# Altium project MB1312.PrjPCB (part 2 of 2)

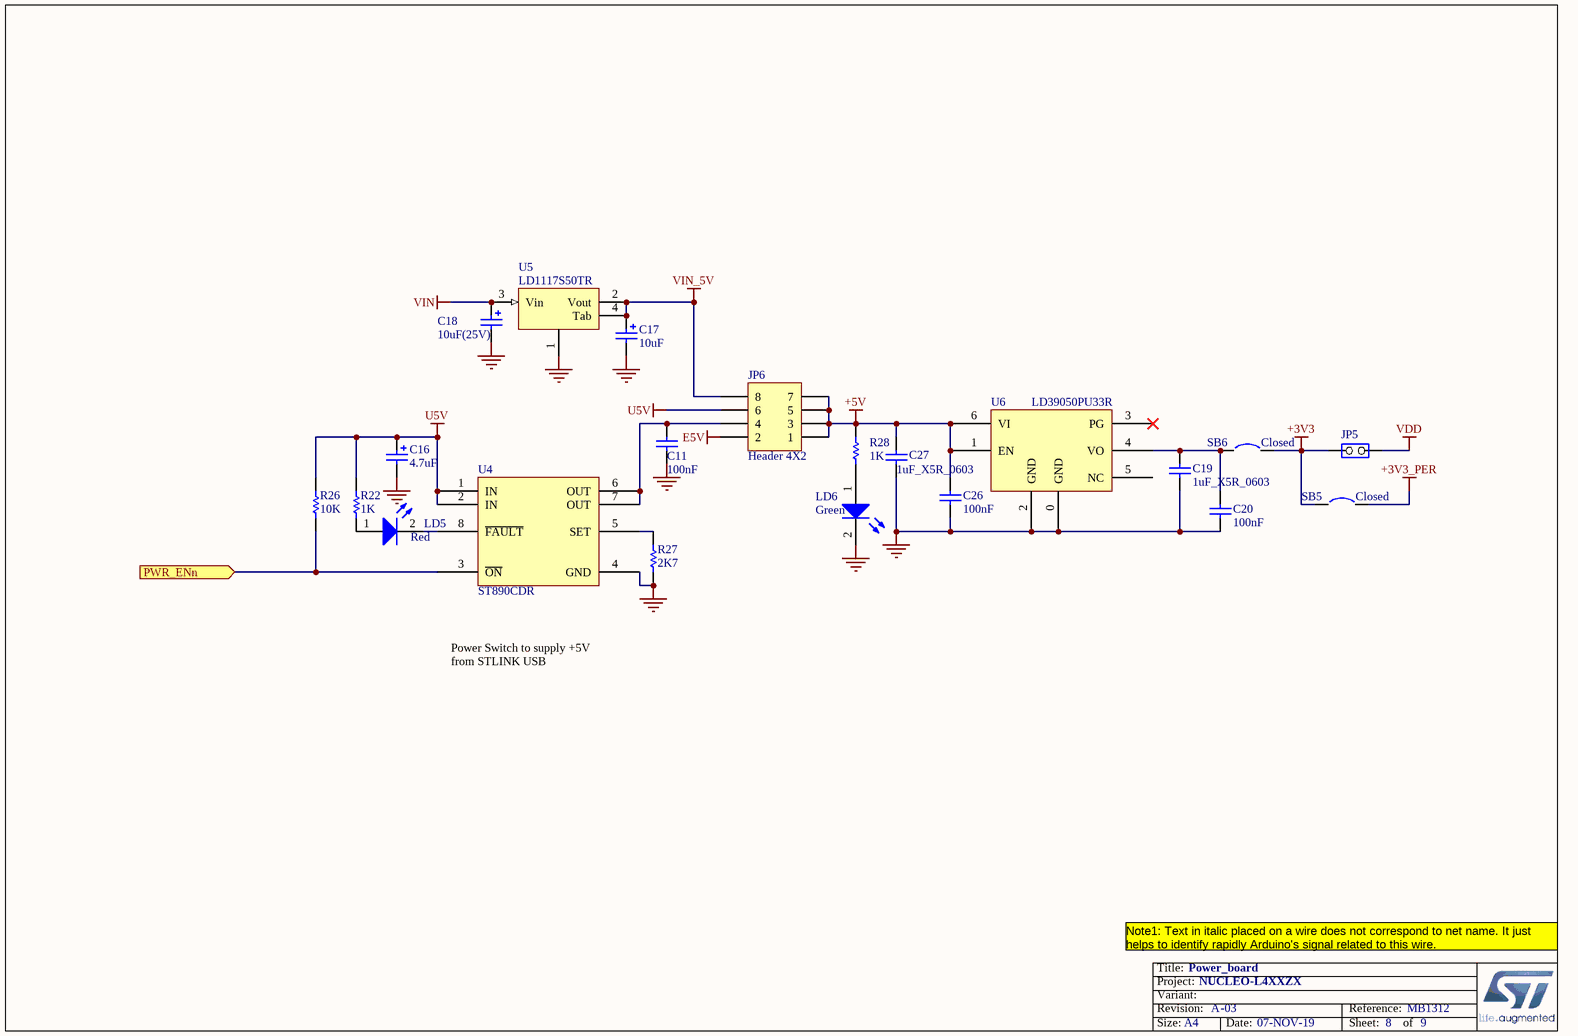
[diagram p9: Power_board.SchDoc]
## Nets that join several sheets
+3V3: Connectors (CN8.7 CN11.16 SB111.1), Power_board (JP5.1 SB5.1 SB6.2)
+3V3_PER: Connectors (SB110.1 U8.5), ST-Link_V2-1 (R23.1), USB (R41.2 R45.2 R51.1), Power_board (SB5.2)
+5V: Connectors (CN8.9 CN11.18), ST-Link_V2-1 (D2.1), USB (U12.5), Power_board (9 pins)
AGND: Connectors (C45.2 CN10.3 CN12.32), STM32_microcontroller_power (7 pins)
AVDD: Connectors (CN10.1), STM32_microcontroller_power (5 pins)
E5V: Connectors (CN11.6), ST-Link_V2-1 (D3.1), Power_board (JP6.2)
GND: Connectors (27 pins), Power_SMPS (27 pins), ST-Link_V2-1 (48 pins), USB (15 pins), STM32_microcontroller_IOs (7 pins), STM32_microcontroller_power (33 pins), Power_board (14 pins)
U5V: Connectors (CN12.8), ST-Link_V2-1 (5 pins), Power_board (6 pins)
VBAT: Connectors (CN11.33), STM32_microcontroller_power (C60.1 SB154.2 U11.6)
VDD: Connectors (CN11.5), Power_SMPS (5 pins), STM32_microcontroller_power (8 pins), Power_board (JP5.2)
VDD_1V2: Power_SMPS (SB2.2 SB3.1 SB11.2), STM32_microcontroller_IOs (C39.2 C55.2 SB15.2 SB139.2)
VDD_MCU: Connectors (SB112.1), Power_SMPS (SB19.2 SB122.2 SB127.2), ST-Link_V2-1 (C44.1 U14.8), STM32_microcontroller_IOs (B1.2 B1.3 R44.1), STM32_microcontroller_power (21 pins)
VIN: Connectors (CN8.15 CN11.24), Power_board (C18.1 U5.3)
VIN_5V: ST-Link_V2-1 (D4.1), Power_board (C17.1 JP6.8 U5.2 U5.4)
VREF+: Connectors (C45.1 SB119.1), STM32_microcontroller_power (C56.1 C57.1 SB149.2 U11.32)
MCO: ST-Link_V2-1 (SB109.1), STM32_microcontroller_power (SB148.2)
NetC42_1: USB (6 pins), STM32_microcontroller_IOs (R54.1)
NetCN6_1: ST-Link_V2-1 (CN6.1 U2.13), STM32_microcontroller_IOs (SB131.2)
NetCN6_2: ST-Link_V2-1 (CN6.2 U2.12), STM32_microcontroller_IOs (SB130.2)
NetCN14_2: USB (CN14.2 U13.1 U13.6), STM32_microcontroller_IOs (SB142.1)
NetCN14_3: USB (CN14.3 R50.1 U13.3 U13.4), STM32_microcontroller_IOs (SB143.1)
NetCN14_4: USB (CN14.4 D6.1), STM32_microcontroller_IOs (SB134.1)
NetR26_2: ST-Link_V2-1 (U2.28), Power_board (R26.2 U4.3)
NRST: Connectors (CN8.5 CN11.14), ST-Link_V2-1 (JP3.2), STM32_microcontroller_power (B2.2 B2.3 C41.2 U11.25)
PA0: Connectors (CN11.28 SB179.1), STM32_microcontroller_IOs (SB178.2 U11.34)
PA1: Connectors (CN10.11 CN11.30), STM32_microcontroller_IOs (U11.35)
PA2: Connectors (CN12.35 SB150.1), STM32_microcontroller_IOs (U11.36)
PA3: Connectors (CN9.1 CN12.37), STM32_microcontroller_IOs (U11.37)
PA4: Connectors (CN11.32 SB126.1 SB133.1), STM32_microcontroller_IOs (U11.40)
PA5: Connectors (CN7.10 CN12.11 SB123.2), STM32_microcontroller_IOs (U11.41)
PA6: Connectors (CN7.12 CN12.13), STM32_microcontroller_IOs (U11.42)
PA7: Connectors (CN7.14 CN12.15), STM32_microcontroller_IOs (U11.43)
PA8: Connectors (CN12.23), STM32_microcontroller_IOs (TP1.1 U11.100)
PA9: Connectors (CN12.21), STM32_microcontroller_IOs (SB135.2 U11.101)
PA10: Connectors (CN12.33), STM32_microcontroller_IOs (SB134.2 U11.102)
PA11: Connectors (CN12.14), STM32_microcontroller_IOs (SB142.2 U11.103)
PA12: Connectors (CN12.12), STM32_microcontroller_IOs (SB143.2 U11.104)
PA13: Connectors (CN11.13), ST-Link_V2-1 (SB106.1), STM32_microcontroller_IOs (U11.105)
PA14: Connectors (CN11.15), ST-Link_V2-1 (SB102.1), STM32_microcontroller_IOs (U11.109)
PA15: Connectors (CN11.17), STM32_microcontroller_IOs (U11.110)
PB0: Connectors (SB144.2 SB159.1 SB182.1), STM32_microcontroller_IOs (U11.46)
PB1: Connectors (CN10.7 CN12.24), STM32_microcontroller_IOs (U11.47)
PB2: Connectors (CN9.13 CN12.22), STM32_microcontroller_IOs (U11.48)
PB3: Connectors (CN7.15 CN12.31), ST-Link_V2-1 (SB141.2), STM32_microcontroller_IOs (SB161.2 SB162.2)
PB4: Connectors (CN12.27 SB128.1 SB140.1), STM32_microcontroller_IOs (SB163.2 SB164.2)
PB5: Connectors (CN7.13 CN12.29), STM32_microcontroller_IOs (SB165.2 SB176.2)
PB6: Connectors (CN9.15 CN12.17), STM32_microcontroller_IOs (SB174.2 SB175.2)
PB7: Connectors (CN11.21), STM32_microcontroller_IOs (R30.1 SB172.2 SB173.2)
PB8: Connectors (CN7.2 CN12.3 SB153.2), STM32_microcontroller_IOs (SB181.2), STM32_microcontroller_power (SB184.2)
PB9: Connectors (CN7.4 CN12.5 SB151.2), STM32_microcontroller_IOs (SB185.2 SB186.2)
PB10: Connectors (CN12.25 SB155.1 SB188.2), STM32_microcontroller_IOs (U11.69)
PB11: Connectors (CN10.34 CN12.18), STM32_microcontroller_IOs (SB138.2)
PB12: Connectors (CN7.7 CN12.16), STM32_microcontroller_IOs (U11.73)
PB13: Connectors (CN7.5 CN12.30), STM32_microcontroller_IOs (U11.74)
PB14: Connectors (CN12.28), STM32_microcontroller_IOs (SB132.1 U11.75)
PB15: Connectors (CN7.3 CN12.26), STM32_microcontroller_IOs (U11.76)
PC0: Connectors (CN9.3 CN11.38), STM32_microcontroller_IOs (U11.26)
PC1: Connectors (CN9.7 CN11.36), STM32_microcontroller_IOs (U11.27)
PC2: Connectors (CN10.9 CN11.35), STM32_microcontroller_IOs (U11.28)
PC3: Connectors (CN9.5 CN11.37), STM32_microcontroller_IOs (U11.29)
PC4: Connectors (CN9.9 CN12.34 SB151.1), STM32_microcontroller_IOs (U11.44)
PC5: Connectors (CN9.11 CN12.6 SB153.1), STM32_microcontroller_IOs (U11.45)
PC6: Connectors (CN7.1 CN12.4), STM32_microcontroller_IOs (U11.96)
PC7: Connectors (CN12.19 SB124.1), STM32_microcontroller_IOs (U11.97)
PC8: Connectors (CN8.2 SB137.1), STM32_microcontroller_IOs (U11.98)
PC9: Connectors (CN8.4 SB136.1), STM32_microcontroller_IOs (U11.99)
PC10: Connectors (CN8.6 CN11.1), STM32_microcontroller_IOs (U11.111)
PC11: Connectors (CN8.8 CN11.2), STM32_microcontroller_IOs (U11.112)
PC12: Connectors (CN8.10 CN11.3), STM32_microcontroller_IOs (U11.113)
PC13: Connectors (CN11.23), STM32_microcontroller_IOs (SB197.1 U11.7)
PC14: Connectors (SB145.1), STM32_microcontroller_IOs (R39.2 U11.8)
PC15: Connectors (SB146.1), STM32_microcontroller_IOs (R40.2 U11.9)
PD0: Connectors (CN9.25 CN11.57), STM32_microcontroller_IOs (U11.114)
PD1: Connectors (CN9.27 CN11.55), STM32_microcontroller_IOs (U11.115)
PD2: Connectors (CN8.12 CN11.4), STM32_microcontroller_IOs (U11.116)
PD3: Connectors (CN9.10 CN11.40), STM32_microcontroller_IOs (U11.117)
PD4: Connectors (CN9.8 CN11.39), STM32_microcontroller_IOs (U11.118)
PD5: Connectors (CN9.6 CN11.41), STM32_microcontroller_IOs (U11.119)
PD6: Connectors (CN9.4 CN11.43), STM32_microcontroller_IOs (U11.122)
PD7: Connectors (CN9.2 CN11.45), STM32_microcontroller_IOs (U11.123)
PD8: Connectors (CN10.14 CN12.10), STM32_microcontroller_IOs (U11.77)
PD9: Connectors (CN10.16 CN11.69), STM32_microcontroller_IOs (U11.78)
PD10: Connectors (CN12.65), STM32_microcontroller_IOs (U11.79)
PD11: Connectors (CN12.45), STM32_microcontroller_IOs (U11.80)
PD12: Connectors (CN12.43), STM32_microcontroller_IOs (U11.81)
PD13: Connectors (CN12.41), STM32_microcontroller_IOs (U11.82)
PD14: Connectors (CN7.16 CN12.46), STM32_microcontroller_IOs (U11.85)
PD15: Connectors (CN7.18 CN12.48), STM32_microcontroller_IOs (U11.86)
PE0: Connectors (CN10.33 CN12.64), STM32_microcontroller_IOs (SB187.2 SB190.1)
PE1: Connectors (CN11.61), STM32_microcontroller_IOs (SB14.1 SB189.1)
PE2: Connectors (CN9.14 CN11.46), STM32_microcontroller_IOs (U11.1)
PE3: Connectors (CN9.22 CN11.47), STM32_microcontroller_IOs (U11.2)
PE4: Connectors (CN9.16 CN11.48), STM32_microcontroller_IOs (U11.3)
PE5: Connectors (CN9.18 CN11.50), STM32_microcontroller_IOs (U11.4)
PE6: Connectors (CN9.20 CN11.62), STM32_microcontroller_IOs (U11.5)
PE7: Connectors (CN10.20 CN12.44), STM32_microcontroller_IOs (U11.58)
PE8: Connectors (CN10.18 CN12.40), STM32_microcontroller_IOs (U11.59)
PE9: Connectors (CN10.4 CN12.52), STM32_microcontroller_IOs (U11.60)
PE10: Connectors (CN10.24 CN12.47), STM32_microcontroller_IOs (U11.63)
PE11: Connectors (CN10.6 CN12.56), STM32_microcontroller_IOs (U11.64)
PE12: Connectors (CN12.49 SB168.1 SB169.2), STM32_microcontroller_IOs (U11.65)
PE13: Connectors (CN10.10 CN12.55), STM32_microcontroller_IOs (U11.66)
PE14: Connectors (CN12.51 SB170.1 SB177.2), STM32_microcontroller_IOs (U11.67)
PE15: Connectors (CN12.53 SB157.1 SB180.2), STM32_microcontroller_IOs (U11.68)
PF0: Connectors (CN9.21 CN11.53), STM32_microcontroller_IOs (U11.10)
PF1: Connectors (CN9.19 CN11.51), STM32_microcontroller_IOs (U11.11)
PF2: Connectors (CN9.17 CN11.52), STM32_microcontroller_IOs (U11.12)
PF3: Connectors (CN8.14 CN12.58), STM32_microcontroller_IOs (U11.13)
PF4: Connectors (CN12.38), STM32_microcontroller_IOs (U11.14)
PF5: Connectors (CN8.16 CN12.36), STM32_microcontroller_IOs (U11.15)
PF6: Connectors (CN11.9), STM32_microcontroller_IOs (U11.18)
PF7: Connectors (CN9.26 CN11.11), STM32_microcontroller_IOs (U11.19)
PF8: Connectors (CN9.24 CN11.54), STM32_microcontroller_IOs (U11.20)
PF9: Connectors (CN9.28 CN11.56), STM32_microcontroller_IOs (U11.21)
PF10: Connectors (CN12.42), STM32_microcontroller_IOs (U11.22)
PF11: Connectors (CN12.62), STM32_microcontroller_IOs (U11.49)
PF12: Connectors (CN7.20 CN12.59), STM32_microcontroller_IOs (U11.50)
PF13: Connectors (CN10.2 CN12.57), STM32_microcontroller_IOs (U11.53)
PF14: Connectors (CN10.8 CN12.50), STM32_microcontroller_IOs (U11.54)
PF15: Connectors (CN10.12 CN12.60), STM32_microcontroller_IOs (U11.55)
PG0: Connectors (CN9.29 CN11.59), STM32_microcontroller_IOs (U11.56)
PG1: Connectors (CN9.30 CN11.58), STM32_microcontroller_IOs (U11.57)
PG2: Connectors (CN11.42), STM32_microcontroller_IOs (U11.87)
PG3: Connectors (CN11.44), STM32_microcontroller_IOs (U11.88)
PG4: Connectors (CN12.69), STM32_microcontroller_IOs (U11.89)
PG5: Connectors (CN12.68), STM32_microcontroller_IOs (JP4.2 U11.90)
PG6: Connectors (CN12.70), STM32_microcontroller_IOs (U11.91)
PG7: Connectors (SB195.1), STM32_microcontroller_IOs (SB131.1 U11.92)
PG8: Connectors (SB193.2), STM32_microcontroller_IOs (SB130.1 U11.93)
PG9: Connectors (CN11.63), STM32_microcontroller_IOs (U11.124)
PG10: Connectors (SB192.2), Power_SMPS (CN13.2 SB10.1 SB118.1), STM32_microcontroller_IOs (U11.125)
PG11: Connectors (SB196.2), Power_SMPS (CN13.4 SB16.2), STM32_microcontroller_IOs (U11.126)
PG12: Connectors (SB191.1), Power_SMPS (CN13.8 SB18.2), STM32_microcontroller_IOs (U11.127)
PG13: Connectors (SB194.2), Power_SMPS (CN13.6 SB17.2), STM32_microcontroller_IOs (U11.128)
PG14: Connectors (CN12.61), STM32_microcontroller_IOs (U11.129)
PG15: Connectors (CN11.64), STM32_microcontroller_IOs (SB160.2)
PH0: Connectors (SB147.1), STM32_microcontroller_power (SB12.2 SB148.1 U11.23)
PH1: Connectors (SB156.1), STM32_microcontroller_power (SB13.2 U11.24)
PH3-BOOT0: Connectors (CN11.7), STM32_microcontroller_IOs (SB171.2), STM32_microcontroller_power (R38.1 SB183.2)

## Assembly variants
L4P5ZG: not fitted C7 C21 C22 C23 C24 C25 C37 C38 C40 C43 C44 C45 C46 C47 C48 CN13 JP2 L1 L2 R1 R4 R32 R33 R34 R35 R46 R47 R50 R53 SB1 SB2 SB3 SB4 SB7 SB8 SB9 SB10 SB11 SB12 SB13 SB15 SB16 SB17 SB18 SB19 SB101 SB103 SB105 SB107 SB109 SB110 SB111 SB113 SB114 SB115 SB116 SB117 SB118 SB119 SB120 SB121 SB123 SB125 SB127 SB129 SB139 SB145 SB146 SB148 SB151 SB153 SB161 SB164 SB165 SB167 SB171 SB173 SB175 SB178 SB184 SB186 SB187 SB189 SB199 SB201 U7 U9 U10 U14 U15 U16 X3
